VERSION 5.7 ;
  NOWIREEXTENSIONATPIN ON ;
  DIVIDERCHAR "/" ;
  BUSBITCHARS "[]" ;
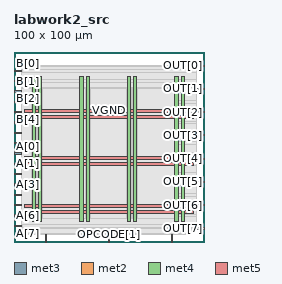
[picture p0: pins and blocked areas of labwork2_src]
MACRO labwork2_src
  CLASS BLOCK ;
  FOREIGN labwork2_src ;
  ORIGIN 0.000 0.000 ;
  SIZE 100.000 BY 100.000 ;
  PIN A[0]
    DIRECTION INPUT ;
    USE SIGNAL ;
    ANTENNAGATEAREA 0.196500 ;
    PORT
      LAYER met3 ;
        RECT 0.000 46.280 4.000 46.880 ;
    END
  END A[0]
  PIN A[1]
    DIRECTION INPUT ;
    USE SIGNAL ;
    ANTENNAGATEAREA 0.213000 ;
    PORT
      LAYER met3 ;
        RECT 0.000 40.840 4.000 41.440 ;
    END
  END A[1]
  PIN A[2]
    DIRECTION INPUT ;
    USE SIGNAL ;
    ANTENNAGATEAREA 0.213000 ;
    PORT
      LAYER met3 ;
        RECT 0.000 35.400 4.000 36.000 ;
    END
  END A[2]
  PIN A[3]
    DIRECTION INPUT ;
    USE SIGNAL ;
    ANTENNAGATEAREA 0.159000 ;
    PORT
      LAYER met3 ;
        RECT 0.000 29.960 4.000 30.560 ;
    END
  END A[3]
  PIN A[4]
    DIRECTION INPUT ;
    USE SIGNAL ;
    ANTENNAGATEAREA 0.213000 ;
    PORT
      LAYER met3 ;
        RECT 0.000 24.520 4.000 25.120 ;
    END
  END A[4]
  PIN A[5]
    DIRECTION INPUT ;
    USE SIGNAL ;
    ANTENNAGATEAREA 0.159000 ;
    PORT
      LAYER met3 ;
        RECT 0.000 19.080 4.000 19.680 ;
    END
  END A[5]
  PIN A[6]
    DIRECTION INPUT ;
    USE SIGNAL ;
    ANTENNAGATEAREA 0.159000 ;
    PORT
      LAYER met3 ;
        RECT 0.000 13.640 4.000 14.240 ;
    END
  END A[6]
  PIN A[7]
    DIRECTION INPUT ;
    USE SIGNAL ;
    ANTENNAGATEAREA 0.159000 ;
    PORT
      LAYER met3 ;
        RECT 0.000 8.200 4.000 8.800 ;
    END
  END A[7]
  PIN B[0]
    DIRECTION INPUT ;
    USE SIGNAL ;
    ANTENNAGATEAREA 0.126000 ;
    PORT
      LAYER met3 ;
        RECT 0.000 89.800 4.000 90.400 ;
    END
  END B[0]
  PIN B[1]
    DIRECTION INPUT ;
    USE SIGNAL ;
    ANTENNAGATEAREA 0.213000 ;
    PORT
      LAYER met3 ;
        RECT 0.000 84.360 4.000 84.960 ;
    END
  END B[1]
  PIN B[2]
    DIRECTION INPUT ;
    USE SIGNAL ;
    ANTENNAGATEAREA 0.213000 ;
    PORT
      LAYER met3 ;
        RECT 0.000 78.920 4.000 79.520 ;
    END
  END B[2]
  PIN B[3]
    DIRECTION INPUT ;
    USE SIGNAL ;
    ANTENNAGATEAREA 0.213000 ;
    PORT
      LAYER met3 ;
        RECT 0.000 73.480 4.000 74.080 ;
    END
  END B[3]
  PIN B[4]
    DIRECTION INPUT ;
    USE SIGNAL ;
    ANTENNAGATEAREA 0.213000 ;
    PORT
      LAYER met3 ;
        RECT 0.000 68.040 4.000 68.640 ;
    END
  END B[4]
  PIN B[5]
    DIRECTION INPUT ;
    USE SIGNAL ;
    ANTENNAGATEAREA 0.159000 ;
    PORT
      LAYER met3 ;
        RECT 0.000 62.600 4.000 63.200 ;
    END
  END B[5]
  PIN B[6]
    DIRECTION INPUT ;
    USE SIGNAL ;
    ANTENNAGATEAREA 0.213000 ;
    PORT
      LAYER met3 ;
        RECT 0.000 57.160 4.000 57.760 ;
    END
  END B[6]
  PIN B[7]
    DIRECTION INPUT ;
    USE SIGNAL ;
    ANTENNAGATEAREA 0.213000 ;
    PORT
      LAYER met3 ;
        RECT 0.000 51.720 4.000 52.320 ;
    END
  END B[7]
  PIN OPCODE[0]
    DIRECTION INPUT ;
    USE SIGNAL ;
    ANTENNAGATEAREA 0.213000 ;
    PORT
      LAYER met2 ;
        RECT 82.890 0.000 83.170 4.000 ;
    END
  END OPCODE[0]
  PIN OPCODE[1]
    DIRECTION INPUT ;
    USE SIGNAL ;
    ANTENNAGATEAREA 0.213000 ;
    PORT
      LAYER met2 ;
        RECT 49.770 0.000 50.050 4.000 ;
    END
  END OPCODE[1]
  PIN OPCODE[2]
    DIRECTION INPUT ;
    USE SIGNAL ;
    ANTENNAGATEAREA 0.213000 ;
    PORT
      LAYER met2 ;
        RECT 16.650 0.000 16.930 4.000 ;
    END
  END OPCODE[2]
  PIN OUT[0]
    DIRECTION OUTPUT ;
    USE SIGNAL ;
    ANTENNADIFFAREA 0.445500 ;
    PORT
      LAYER met3 ;
        RECT 96.000 92.520 100.000 93.120 ;
    END
  END OUT[0]
  PIN OUT[1]
    DIRECTION OUTPUT ;
    USE SIGNAL ;
    ANTENNADIFFAREA 0.445500 ;
    PORT
      LAYER met3 ;
        RECT 96.000 80.280 100.000 80.880 ;
    END
  END OUT[1]
  PIN OUT[2]
    DIRECTION OUTPUT ;
    USE SIGNAL ;
    ANTENNADIFFAREA 0.445500 ;
    PORT
      LAYER met3 ;
        RECT 96.000 68.040 100.000 68.640 ;
    END
  END OUT[2]
  PIN OUT[3]
    DIRECTION OUTPUT ;
    USE SIGNAL ;
    ANTENNADIFFAREA 0.445500 ;
    PORT
      LAYER met3 ;
        RECT 96.000 55.800 100.000 56.400 ;
    END
  END OUT[3]
  PIN OUT[4]
    DIRECTION OUTPUT ;
    USE SIGNAL ;
    ANTENNADIFFAREA 0.445500 ;
    PORT
      LAYER met3 ;
        RECT 96.000 43.560 100.000 44.160 ;
    END
  END OUT[4]
  PIN OUT[5]
    DIRECTION OUTPUT ;
    USE SIGNAL ;
    ANTENNADIFFAREA 0.445500 ;
    PORT
      LAYER met3 ;
        RECT 96.000 31.320 100.000 31.920 ;
    END
  END OUT[5]
  PIN OUT[6]
    DIRECTION OUTPUT ;
    USE SIGNAL ;
    ANTENNADIFFAREA 0.445500 ;
    PORT
      LAYER met3 ;
        RECT 96.000 19.080 100.000 19.680 ;
    END
  END OUT[6]
  PIN OUT[7]
    DIRECTION OUTPUT ;
    USE SIGNAL ;
    ANTENNADIFFAREA 0.445500 ;
    PORT
      LAYER met3 ;
        RECT 96.000 6.840 100.000 7.440 ;
    END
  END OUT[7]
  PIN VGND
    DIRECTION INOUT ;
    USE GROUND ;
    PORT
      LAYER met4 ;
        RECT 13.020 10.640 14.620 87.280 ;
    END
    PORT
      LAYER met4 ;
        RECT 38.020 10.640 39.620 87.280 ;
    END
    PORT
      LAYER met4 ;
        RECT 63.020 10.640 64.620 87.280 ;
    END
    PORT
      LAYER met4 ;
        RECT 88.020 10.640 89.620 87.280 ;
    END
    PORT
      LAYER met5 ;
        RECT 5.280 18.380 94.540 19.980 ;
    END
    PORT
      LAYER met5 ;
        RECT 5.280 43.380 94.540 44.980 ;
    END
    PORT
      LAYER met5 ;
        RECT 5.280 68.380 94.540 69.980 ;
    END
  END VGND
  PIN VPWR
    DIRECTION INOUT ;
    USE POWER ;
    PORT
      LAYER met4 ;
        RECT 9.720 10.640 11.320 87.280 ;
    END
    PORT
      LAYER met4 ;
        RECT 34.720 10.640 36.320 87.280 ;
    END
    PORT
      LAYER met4 ;
        RECT 59.720 10.640 61.320 87.280 ;
    END
    PORT
      LAYER met4 ;
        RECT 84.720 10.640 86.320 87.280 ;
    END
    PORT
      LAYER met5 ;
        RECT 5.280 15.080 94.540 16.680 ;
    END
    PORT
      LAYER met5 ;
        RECT 5.280 40.080 94.540 41.680 ;
    END
    PORT
      LAYER met5 ;
        RECT 5.280 65.080 94.540 66.680 ;
    END
  END VPWR
  OBS
      LAYER nwell ;
        RECT 5.330 10.795 94.490 87.125 ;
      LAYER li1 ;
        RECT 5.520 10.795 94.300 87.125 ;
      LAYER met1 ;
        RECT 4.210 9.560 94.300 88.020 ;
      LAYER met2 ;
        RECT 4.230 4.280 93.280 93.005 ;
        RECT 4.230 4.000 16.370 4.280 ;
        RECT 17.210 4.000 49.490 4.280 ;
        RECT 50.330 4.000 82.610 4.280 ;
        RECT 83.450 4.000 93.280 4.280 ;
      LAYER met3 ;
        RECT 3.750 92.120 95.600 92.985 ;
        RECT 3.750 90.800 96.000 92.120 ;
        RECT 4.400 89.400 96.000 90.800 ;
        RECT 3.750 85.360 96.000 89.400 ;
        RECT 4.400 83.960 96.000 85.360 ;
        RECT 3.750 81.280 96.000 83.960 ;
        RECT 3.750 79.920 95.600 81.280 ;
        RECT 4.400 79.880 95.600 79.920 ;
        RECT 4.400 78.520 96.000 79.880 ;
        RECT 3.750 74.480 96.000 78.520 ;
        RECT 4.400 73.080 96.000 74.480 ;
        RECT 3.750 69.040 96.000 73.080 ;
        RECT 4.400 67.640 95.600 69.040 ;
        RECT 3.750 63.600 96.000 67.640 ;
        RECT 4.400 62.200 96.000 63.600 ;
        RECT 3.750 58.160 96.000 62.200 ;
        RECT 4.400 56.800 96.000 58.160 ;
        RECT 4.400 56.760 95.600 56.800 ;
        RECT 3.750 55.400 95.600 56.760 ;
        RECT 3.750 52.720 96.000 55.400 ;
        RECT 4.400 51.320 96.000 52.720 ;
        RECT 3.750 47.280 96.000 51.320 ;
        RECT 4.400 45.880 96.000 47.280 ;
        RECT 3.750 44.560 96.000 45.880 ;
        RECT 3.750 43.160 95.600 44.560 ;
        RECT 3.750 41.840 96.000 43.160 ;
        RECT 4.400 40.440 96.000 41.840 ;
        RECT 3.750 36.400 96.000 40.440 ;
        RECT 4.400 35.000 96.000 36.400 ;
        RECT 3.750 32.320 96.000 35.000 ;
        RECT 3.750 30.960 95.600 32.320 ;
        RECT 4.400 30.920 95.600 30.960 ;
        RECT 4.400 29.560 96.000 30.920 ;
        RECT 3.750 25.520 96.000 29.560 ;
        RECT 4.400 24.120 96.000 25.520 ;
        RECT 3.750 20.080 96.000 24.120 ;
        RECT 4.400 18.680 95.600 20.080 ;
        RECT 3.750 14.640 96.000 18.680 ;
        RECT 4.400 13.240 96.000 14.640 ;
        RECT 3.750 9.200 96.000 13.240 ;
        RECT 4.400 7.840 96.000 9.200 ;
        RECT 4.400 7.800 95.600 7.840 ;
        RECT 3.750 6.975 95.600 7.800 ;
      LAYER met4 ;
        RECT 3.975 12.415 9.320 80.745 ;
        RECT 11.720 12.415 12.620 80.745 ;
        RECT 15.020 12.415 34.320 80.745 ;
        RECT 36.720 12.415 37.620 80.745 ;
        RECT 40.020 12.415 59.320 80.745 ;
        RECT 61.720 12.415 62.620 80.745 ;
        RECT 65.020 12.415 84.320 80.745 ;
  END
END labwork2_src
END LIBRARY

